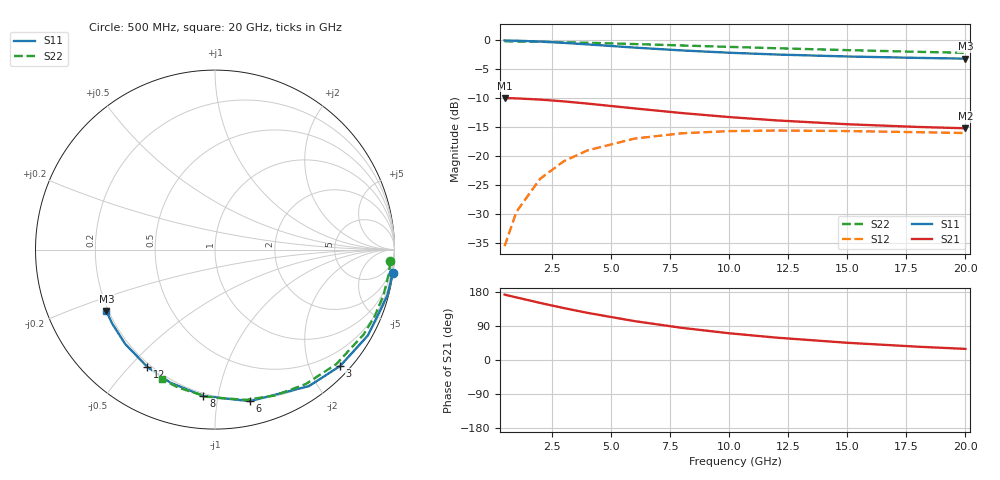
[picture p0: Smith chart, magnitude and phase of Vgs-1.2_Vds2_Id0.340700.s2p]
# Hz S RI R 50
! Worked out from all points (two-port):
!   12 points, 500 MHz to 20 GHz, reference 50 ohm
!   highest |S21| = -9.98 dB at 500 MHz (marker M1); lowest = -15.2 dB at 20 GHz (marker M2)
!   |S21| within 3 dB of the highest: start of sweep to 9.178 GHz
!   lowest |S11| = -3.2 dB at 20 GHz (marker M3), VSWR 5.56, Z = 9.6 - j12.7 ohm
!   |S11| at or under -10 dB: nowhere
!   |S22| runs from -2.2 to -0.2 dB; largest |S21 - S12| = 0.32
!   S11 on the Smith chart (normalised r, x): 500 MHz: 0, -15; 3 GHz: 0.18, -2.53; 6 GHz: 0.18, -1.24; 8 GHz: 0.18, -0.91; 12 GHz: 0.19, -0.56; 20 GHz: 0.19, -0.25
5e8  0.99 -0.1299  -0.3143 0.0412  0.00158 0.0165  0.9773 -0.0654
1e9  0.9605 -0.2555  -0.3044 0.0808  0.00621 0.0323  0.9694 -0.1301
2e9  0.8516 -0.4785  -0.2682 0.1505  0.0231 0.0591  0.9385 -0.2549
3e9  0.6973 -0.6483  -0.2173 0.2021  0.0466 0.0769  0.8902 -0.3701
4e9  0.5236 -0.7607  -0.1608 0.2342  0.072 0.0853  0.8277 -0.4734
6e9  0.1936 -0.8444  -0.0563 0.2518  0.1164 0.0805  0.6754 -0.6384
8e9  -0.0645 -0.816  0.0211 0.2343  0.145 0.0608  0.5049 -0.7495
1e10  -0.2485 -0.7415  0.0722 0.2048  0.1596 0.0383  0.3344 -0.8125
1.2e10  -0.3767 -0.654  0.1046 0.1742  0.1651 0.018  0.1743 -0.8371
1.5e10  -0.5005 -0.5256  0.1321 0.1341  0.1643 -0.00584  -0.0351 -0.8226
1.8e10  -0.5734 -0.411  0.146 0.1024  0.159 -0.0225  -0.2035 -0.7696
2e10  -0.6046 -0.3429  0.1514 0.0851  0.1549 -0.0308  -0.2947 -0.7223
